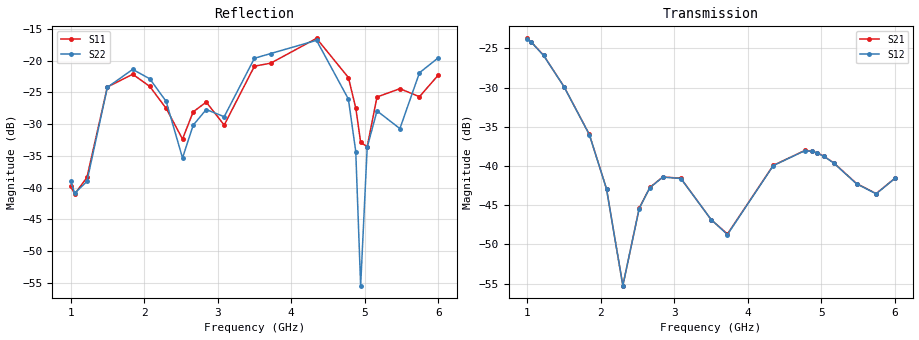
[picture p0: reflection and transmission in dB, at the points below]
!Agilent Technologies,E8364B,MY43040528,A.07.50.67
!Agilent E8364B: A.07.50.67
!Date: Sunday, March 01, 2026 20:39:24
!Correction: S11(Full 2 Port(1,2))
!S21(Full 2 Port(1,2))
!S12(Full 2 Port(1,2))
!S22(Full 2 Port(1,2))
!S2P File: Measurements: S11, S21, S12, S22:
# Hz S  dB  R 50
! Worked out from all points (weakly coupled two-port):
!   451 points, 1 GHz to 6 GHz, reference 50 ohm
!   highest |S21| = -23.72 dB at 1 GHz (marker M1); lowest = -55.3 dB at 2.3 GHz (marker M2)
!   lowest |S11| = -41.0 dB at 1.056 GHz (marker M3), VSWR 1.02, Z = 49.8 + j0.852 ohm
!   |S11| at or under -10 dB: start of sweep to end of sweep
!   |S22| runs from -55.5 to -16.1 dB; largest |S21 - S12| = 0.00019
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1e9  -39.74 78.5  -23.72 148.7  -23.75 148.7  -39.04 16.1
1.055556e9  -41.03 105.5  -24.19 116.6  -24.21 116.6  -40.90 34.6
1.222222e9  -38.42 163.5  -25.88 20.5  -25.90 20.4  -39.05 91.4
1.5e9  -24.15 153.3  -29.88 -135.3  -29.89 -135.3  -24.20 78.0
1.844444e9  -22.13 92.7  -35.98 38.4  -36.00 38.5  -21.36 0.4
2.077778e9  -24.06 65.4  -42.91 -84.5  -42.93 -84.6  -22.86 -41.4
2.3e9  -27.52 46.2  -55.27 -131.7  -55.26 -131.5  -26.43 -78.6
2.522222e9  -32.36 75.5  -45.39 172.1  -45.44 172.1  -35.34 -67.6
2.666667e9  -28.07 84.6  -42.74 96.6  -42.77 96.6  -30.18 -42.1
2.844444e9  -26.52 62.5  -41.39 0.8  -41.42 0.7  -27.70 -68.9
3.088889e9  -30.15 72.8  -41.57 -132.0  -41.60 -132.1  -28.83 -63.3
3.5e9  -20.86 54.6  -46.84 23.3  -46.83 23.5  -19.61 -113.7
3.722222e9  -20.38 35.7  -48.68 -52.2  -48.75 -52.3  -18.86 -145.2
4.344444e9  -16.47 -38.8  -39.93 13.6  -39.96 13.5  -16.78 107.0
4.777778e9  -22.65 -108.6  -38.00 126.8  -38.03 126.8  -26.05 10.2
4.877778e9  -27.45 -119.6  -38.13 67.6  -38.15 67.7  -34.32 -17.4
4.944444e9  -32.88 -109.8  -38.33 28.0  -38.36 28.0  -55.49 -70.4
5.033333e9  -33.56 -44.6  -38.75 -25.3  -38.76 -25.3  -33.67 129.4
5.166667e9  -25.72 -41.1  -39.59 -106.2  -39.62 -106.1  -27.91 94.7
5.477778e9  -24.41 -85.1  -42.24 53.3  -42.27 53.4  -30.71 72.7
5.744444e9  -25.67 -72.3  -43.52 -138.2  -43.55 -138.2  -21.89 60.2
6e9  -22.26 -82.9  -41.56 42.4  -41.58 42.4  -19.54 5.7
